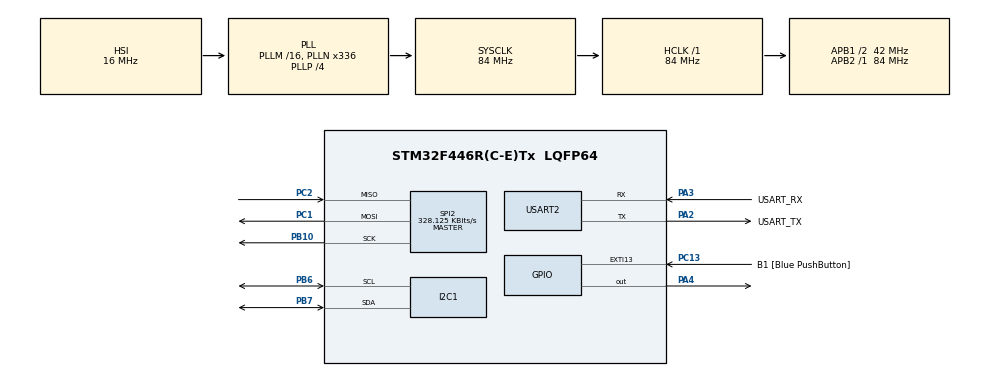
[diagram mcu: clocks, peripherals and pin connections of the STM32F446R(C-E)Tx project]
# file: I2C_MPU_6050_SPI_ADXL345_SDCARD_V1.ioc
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Mcu.Family=STM32F4
Mcu.Name=STM32F446R(C-E)Tx
Mcu.Package=LQFP64
NVIC.PriorityGroup=NVIC_PRIORITYGROUP_0
PA13.GPIO_Label=TMS
PA13.Mode=Serial_Wire
PA13.Signal=SYS_JTMS-SWDIO
PA14.GPIO_Label=TCK
PA14.Mode=Serial_Wire
PA14.Signal=SYS_JTCK-SWCLK
PA2.GPIO_Label=USART_TX
PA2.Mode=Asynchronous
PA2.Signal=USART2_TX
PA3.GPIO_Label=USART_RX
PA3.Mode=Asynchronous
PA3.Signal=USART2_RX
PA4.Signal=GPIO_Output
PB10.Mode=Full_Duplex_Master
PB10.Signal=SPI2_SCK
PB3.GPIO_Label=SWO
PB3.Signal=SYS_JTDO-SWO
PB6.Mode=I2C
PB6.Signal=I2C1_SCL
PB7.Mode=I2C
PB7.Signal=I2C1_SDA
PC1.Mode=Full_Duplex_Master
PC1.Signal=SPI2_MOSI
PC13.GPIO_Label=B1 [Blue PushButton]
PC13.GPIO_ModeDefaultEXTI=GPIO_MODE_IT_FALLING
PC13.Signal=GPXTI13
PC14-OSC32_IN.Mode=LSE-External-Oscillator
PC14-OSC32_IN.Signal=RCC_OSC32_IN
PC15-OSC32_OUT.Mode=LSE-External-Oscillator
PC15-OSC32_OUT.Signal=RCC_OSC32_OUT
PC2.Mode=Full_Duplex_Master
PC2.Signal=SPI2_MISO
PH0-OSC_IN.Mode=HSE-External-Oscillator
PH0-OSC_IN.Signal=RCC_OSC_IN
PH1-OSC_OUT.Mode=HSE-External-Oscillator
PH1-OSC_OUT.Signal=RCC_OSC_OUT
ProjectManager.HeapSize=0x200
ProjectManager.StackSize=0x400
ProjectManager.TargetToolchain=STM32CubeIDE
RCC.48MHZClocksFreq_Value=84000000
RCC.AHBFreq_Value=84000000
RCC.APB1CLKDivider=RCC_HCLK_DIV2
RCC.APB1Freq_Value=42000000
RCC.APB1TimFreq_Value=84000000
RCC.APB2Freq_Value=84000000
RCC.APB2TimFreq_Value=84000000
RCC.CortexFreq_Value=84000000
RCC.FLatency-AdvancedSettings=FLASH_LATENCY_2
RCC.HCLKFreq_Value=84000000
RCC.HSE_VALUE=8000000
RCC.HSI_VALUE=16000000
RCC.PLLN=336
RCC.PLLP=RCC_PLLP_DIV4
RCC.SYSCLKFreq_VALUE=84000000
RCC.SYSCLKSource=RCC_SYSCLKSOURCE_PLLCLK
RCC.USBFreq_Value=168000000
RCC.VCOOutputFreq_Value=336000000
SPI2.BaudRatePrescaler=SPI_BAUDRATEPRESCALER_128
SPI2.CalculateBaudRate=328.125 KBits/s
SPI2.Direction=SPI_DIRECTION_2LINES
SPI2.Mode=SPI_MODE_MASTER
SPI2.VirtualType=VM_MASTER
USART2.VirtualMode=VM_ASYNC
VP_FATFS_VS_Generic.Mode=User_defined
board=NUCLEO-F446RE

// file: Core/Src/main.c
/* USER CODE BEGIN Header */
/**
  ******************************************************************************
  * @file           : main.c
  * @brief          : Main program body
  ******************************************************************************
  * @attention
  *
  * Copyright (c) 2025 STMicroelectronics.
  * All rights reserved.
  *
  * This software is licensed under terms that can be found in the LICENSE file
  * in the root directory of this software component.
  * If no LICENSE file comes with this software, it is provided AS-IS.
  *
  ******************************************************************************
  */
/* USER CODE END Header */

// ===============================
//   INTERCONEXIONES STM32F446RE
// ===============================
//
// --- MPU6050 (I2C1) ---
// VCC   -> 3.3V                  // Alimentación del sensor
// GND   -> GND                   // Tierra
// SDA   -> PB7                   // I2C1_SDA (requiere pull-up 4.7kΩ)
// SCL   -> PB6                   // I2C1_SCL (requiere pull-up 4.7kΩ)
// AD0   -> GND                   // Dirección I2C = 0x68
// INT   -> (no conectado)        // Interrupción opcional
//
//
// --- Tarjeta SD (SPI2) ---
// VCC   -> 3.3V                  // Alimentación (¡no usar 5V!)
// GND   -> GND                   // Tierra
// CS    -> PA4                   // GPIO Output, Chip Select manual
// SCK   -> PB10                  // SPI2_SCK
// MISO  -> PC2                  // SPI2_MISO
// MOSI  -> PC1                  // SPI2_MOSI
//
//====================== INTERCONEXIÓN ADXL345 - STM32F446RE ======================//
// ADXL345        ->  STM32F446RE                // DESCRIPCIÓN
// ----------------------------------------------------------------------------- //
/* VCC           ->  3.3V                        // Alimentación del sensor     */
/* GND           ->  GND                         // Tierra común                */
/* CS            ->  PA9                         // Chip Select (CS) manual     */
/* SCL (CLK)     ->  PA5                         // SPI1_SCK - reloj SPI        */
/* SDA (MOSI)    ->  PA7                         // SPI1_MOSI - datos al sensor */
/* SDO (MISO)    ->  PA6                         // SPI1_MISO - datos al STM32  */
//================================================================================//

// ============================================
//   CONEXIONES STM32F446RE ↔ LCD I2C (PCF8574)
// ============================================
//
// LCD I2C     ↔   STM32F446RE
//
// VCC         ↔   5V               // Alimentación (verifica compatibilidad)
// GND         ↔   GND              // Tierra común
// SDA         ↔   PB7              // I2C1 SDA (requiere pull-up si el módulo no lo tiene)
// SCL         ↔   PB6              // I2C1 SCL (requiere pull-up si el módulo no lo tiene)

#include "main.h"
#include <stdio.h>
#include "stm32f4xx_hal.h"
#include "fatfs.h"
#include <string.h>
#include <stdint.h>
#include "adxl345.h"
#include "API_delay.h"
#include "lcd_i2c.h"

/* USER CODE BEGIN PTD */
typedef enum {
    ESTADO_IDLE,
    ESTADO_MPU,
    ESTADO_ADXL,
    ESTADO_SD,
	ESTADO_BORRAR_SD,
	ESTADO_LEER_SD,
	ESTADO_LCD,
    ESTADO_ERROR
} estado_t;

estado_t estadoActual = ESTADO_IDLE;

/* USER CODE END PTD */

I2C_HandleTypeDef hi2c1;

SPI_HandleTypeDef hspi2;

UART_HandleTypeDef huart2;

delay_t myDelayMPU,myDelayADXL,myDelaySD;

//extern I2C_HandleTypeDef hi2c1;

/* USER CODE BEGIN PV */
// === DEFINICIONES MPU6050 ===
#define MPU6050_ADDR  (0x68 << 1)
#define MPU6050_PWR_MGMT_1  0x6B
#define MPU6050_ACCEL_XOUT_H  0x3B

//extern I2C_HandleTypeDef hi2c1;
//extern UART_HandleTypeDef huart2;
//extern DMA_HandleTypeDef hdma_i2c1_rx;
int16_t AccX, AccY, AccZ, Temp, GyroX, GyroY, GyroZ;
float Ax, Ay, Az, Gx, Gy, Gz, TempC;
char msg[150];
char msg2[128];

// FATFS
FATFS fs;
FATFS *pfs;
FIL fil;
FRESULT fres;
DWORD fre_clust;
uint32_t totalSpace, freeSpace;
char buffer[200];
uint8_t rxChar;
char mensajeRoca[] = "La Roca dice: No te rindas, campeon\n";

int16_t x, y, z;          /**< Variables enteras para datos crudos de aceleración. */
double xg, yg, zg;        /**< Variables para datos de aceleración en g. */
uint8_t data_rec[6];      /**< Arreglo para almacenar los 6 bytes de datos del ADXL345. */

/* USER CODE END PV */
/* USER CODE BEGIN 0 */
void MPU6050_Init(void);
void MPU6050_Read_All(void);

void MPU6050_Init(void)
{
  uint8_t data = 0x00;
  HAL_I2C_Mem_Write(&hi2c1, MPU6050_ADDR, MPU6050_PWR_MGMT_1,
                    I2C_MEMADD_SIZE_8BIT, &data, 1, HAL_MAX_DELAY);
}

void MPU6050_Read_All(void)
{
  uint8_t raw_data[14];

  HAL_I2C_Mem_Read(&hi2c1, MPU6050_ADDR, MPU6050_ACCEL_XOUT_H,I2C_MEMADD_SIZE_8BIT, raw_data, 14, HAL_MAX_DELAY);

  // HAL_I2C_Mem_Read(
  //   &hi2c1,                   // I2C que estás usando (I2C1)
  //   MPU6050_ADDR,            // Dirección del sensor (0x68 << 1 = 0xD0)
  //   MPU6050_ACCEL_XOUT_H,    // Registro inicial: 0x3B (donde comienza AccX)
  //   I2C_MEMADD_SIZE_8BIT,    // Tamaño de dirección del registro (8 bits)
  //   raw_data,                // Buffer donde se guardan los 14 bytes leídos
  //   14,                      // Cantidad de bytes a leer (Acc, Temp, Gyro)
  //   HAL_MAX_DELAY            // Esperar indefinidamente si el bus está ocupado
  // );

    AccX = (raw_data[0] << 8) | raw_data[1];
    AccY = (raw_data[2] << 8) | raw_data[3];
    AccZ = (raw_data[4] << 8) | raw_data[5];
    Temp = (raw_data[6] << 8) | raw_data[7];
    GyroX = (raw_data[8] << 8) | raw_data[9];
    GyroY = (raw_data[10] << 8) | raw_data[11];
    GyroZ = (raw_data[12] << 8) | raw_data[13];

    Ax = AccX / 16384.0f; //convierte a datos crudos en unidades de medidas m/s2
    Ay = AccY / 16384.0f;
    Az = AccZ / 16384.0f;
    TempC = Temp / 340.0f + 36.53f;
    Gx = GyroX / 131.0f;
    Gy = GyroY / 131.0f;
    Gz = GyroZ / 131.0f;

}
/* USER CODE END 0 */

void SystemClock_Config(void);
static void MX_GPIO_Init(void);
static void MX_USART2_UART_Init(void);
static void MX_I2C1_Init(void);
static void MX_SPI2_Init(void);
void MX_FATFS_Init(void);
/* USER CODE BEGIN PFP */
void leerMPU(void);
void leerADXL(void);
void inicializarArchivoSD(void);
void borrarSD(void);
void leerSD(void);

/* USER CODE END PFP */

int main(void)
{

  /* MCU Configuration--------------------------------------------------------*/

  /* Reset of all peripherals, Initializes the Flash interface and the Systick. */
  HAL_Init();

  /* Configure the system clock */
  SystemClock_Config();

  /* Initialize all configured peripherals */
  MX_GPIO_Init();
  MX_USART2_UART_Init();
  MX_I2C1_Init();
  MX_SPI2_Init();
  MX_FATFS_Init();
  /* USER CODE BEGIN 2 */
  MPU6050_Init();
  adxl_init();  /**< Inicializa el acelerómetro ADXL345. */
  HAL_Delay(100);

  delayInit(&myDelayMPU, 1000);
  delayInit(&myDelayADXL, 500);
  delayInit(&myDelaySD, 2000);  // Ej. 2 segundos entre escrituras

  inicializarArchivoSD();

  LCD_Init(&hi2c1);

  /* USER CODE END 2 */

  /* Infinite loop */
  /* USER CODE BEGIN WHILE */
  while (1)
    {
	  switch (estadoActual)
	  {
	      case ESTADO_IDLE:
	          if (HAL_UART_Receive(&huart2, &rxChar, 1, 10) == HAL_OK) {
	              if (rxChar == '1') estadoActual = ESTADO_MPU;
	              else if (rxChar == '2') estadoActual = ESTADO_ADXL;
	              else if (rxChar == '3') estadoActual = ESTADO_SD;
	              else if (rxChar == '4') estadoActual = ESTADO_BORRAR_SD;
	              else if (rxChar == '5') estadoActual = ESTADO_LEER_SD;
	              else if (rxChar == '6') estadoActual = ESTADO_LCD; //NO CONCLUIDO
	              else estadoActual = ESTADO_IDLE;
	          }
	          break;

	      case ESTADO_MPU:
	    	  if (delayRead(&myDelayMPU))
	    	  {
	    		 leerMPU();
				 estadoActual = ESTADO_IDLE;
	    	  }
	          break;

	      case ESTADO_ADXL:
	    	  if (delayRead(&myDelayADXL))
	    	  {
	    		  leerADXL();
				  estadoActual = ESTADO_IDLE;
	    	  }
	          break;

	      case ESTADO_SD:
	    	  if (delayRead(&myDelaySD))
	    	  {
	    		  guardarDatosEnSD();
	    		  estadoActual = ESTADO_IDLE;
	    	  }
	          break;

	      case ESTADO_BORRAR_SD:
	    	  borrarSD();
	    	  break;

	      case ESTADO_LEER_SD:
	    	  leerSD();
	    	  break;

	      case ESTADO_LCD:
	    	   LCD_SendCommand(&hi2c1, 0x01);  // Limpiar pantalla
	    	   HAL_Delay(2);
	    	   LCD_SendString(&hi2c1, "Hola Mundo!");
	      	   estadoActual = ESTADO_IDLE;
	      	   break;

	      case ESTADO_ERROR:
	          HAL_UART_Transmit(&huart2, (uint8_t*)" Error detectado!\r\n", 19, HAL_MAX_DELAY);
	          estadoActual = ESTADO_IDLE;
	          break;

	      default:
	          estadoActual = ESTADO_IDLE;
	          break;
	  }

    }
  /* USER CODE END 3 */
}

void leerMPU(void)
{
  MPU6050_Read_All();
  int bytes = snprintf(msg, sizeof(msg),
						   "MPU Acelerometro[g]:  X=%.4f  Y=%.4f  Z=%.4f\r\n"
						   "MPU Giroscopio[gr/s]: X=%.4f  Y=%.4f  Z=%.4f\r\n"
						   "MPU Temperatura[C]:   %.2f\r\n\r\n",
						   Ax, Ay, Az, Gx, Gy, Gz, TempC);
   if (bytes > 0)
   {
	   HAL_UART_Transmit(&huart2, (uint8_t*)msg, bytes, HAL_MAX_DELAY);
   }
}

void leerADXL(void)
{
	adxl_read(DATA_START_ADDR, data_rec);
	x = ((data_rec[1] << 8) | data_rec[0]);
	y = ((data_rec[3] << 8) | data_rec[2]);
	z = ((data_rec[5] << 8) | data_rec[4]);
	xg = x * 0.0078;
	yg = y * 0.0078;
	zg = z * 0.0078;
	int bytes = snprintf(msg2, sizeof(msg2), "ADXL345[g]: X=%.4f  Y=%.4f  Z=%.4f\r\n\r\n", xg, yg, zg);
	if (bytes > 0)
	{
	  HAL_UART_Transmit(&huart2, (uint8_t*)msg2, bytes, HAL_MAX_DELAY);
	}
}

void inicializarArchivoSD(void)
{
    if (f_mount(&fs, "", 0) != FR_OK) Error_Handler();

    if (f_open(&fil, "la_roca.txt", FA_OPEN_ALWAYS | FA_READ | FA_WRITE) != FR_OK)
        Error_Handler();

    // Opcional: verificar espacio
    if (f_getfree("", &fre_clust, &pfs) != FR_OK) Error_Handler();
    totalSpace = (uint32_t)((pfs->n_fatent - 2) * pfs->csize * 0.5);
    freeSpace = (uint32_t)(fre_clust * pfs->csize * 0.5);
    if (freeSpace < 1) Error_Handler();

    // Escribir datos iniciales
    f_puts("CESE\n", &fil);
    f_puts("STM32F446RE SD Card via SPI2\n", &fil);
    f_puts("Cristo la Roca!!!\r\n", &fil);

    if (f_close(&fil) != FR_OK) Error_Handler();

    // Lectura opcional
    if (f_open(&fil, "la_roca.txt", FA_READ) != FR_OK) Error_Handler();
    while (f_gets(buffer, sizeof(buffer), &fil)) {
    	HAL_UART_Transmit(&huart2, (uint8_t*)buffer, strlen(buffer), HAL_MAX_DELAY);
    }
    if (f_close(&fil) != FR_OK) Error_Handler();

    if (f_mount(NULL, "", 1) != FR_OK) Error_Handler();
}

void guardarDatosEnSD(void)
{
    if (f_mount(&fs, "", 0) != FR_OK) {
        estadoActual = ESTADO_ERROR;
        return;
    }

    if (f_open(&fil, "la_roca.txt", FA_OPEN_APPEND | FA_WRITE) != FR_OK) {
        estadoActual = ESTADO_ERROR;
        return;
    }

    f_puts(msg, &fil);
    f_puts(msg2, &fil);
    f_close(&fil);
    f_mount(NULL, "", 1);

    HAL_UART_Transmit(&huart2, (uint8_t*)"Datos guardados en SD.\r\n", 25, HAL_MAX_DELAY);

}

void borrarSD(void)
{
    if (f_mount(&fs, "", 0) == FR_OK)
    {
        if (f_open(&fil, "la_roca.txt", FA_WRITE | FA_CREATE_ALWAYS) == FR_OK)
        {
            // ✅ Archivo truncado (contenido eliminado)
            f_puts("Archivo reiniciado.\r\n", &fil);  // Opcional: escribir línea de cabecera
            f_close(&fil);
            char msg[] = "Contenido del archivo borrado.\r\n";
            HAL_UART_Transmit(&huart2, (uint8_t*)msg, strlen(msg), HAL_MAX_DELAY);
        }
        else
        {
            estadoActual = ESTADO_ERROR;
            return;
        }
        f_mount(NULL, "", 1);
    } else {
        estadoActual = ESTADO_ERROR;
        return;
    }
    estadoActual = ESTADO_IDLE;
}

void leerSD(void)
{
    if (f_mount(&fs, "", 0) == FR_OK)
    {
        if (f_open(&fil, "la_roca.txt", FA_READ) == FR_OK)
        {
            while (f_gets(buffer, sizeof(buffer), &fil))
            {
                HAL_UART_Transmit(&huart2, (uint8_t*)buffer, strlen(buffer), HAL_MAX_DELAY);
            }
            f_close(&fil);
            char fin[] = "\r\nFin de lectura SD\r\n";
            HAL_UART_Transmit(&huart2, (uint8_t*)fin, strlen(fin), HAL_MAX_DELAY);
        }
        else
        {
            estadoActual = ESTADO_ERROR;
            return;
        }
        f_mount(NULL, "", 1);
    }
    else
    {
        estadoActual = ESTADO_ERROR;
        return;
    }
    estadoActual = ESTADO_IDLE;
}

void SystemClock_Config(void)
{
  RCC_OscInitTypeDef RCC_OscInitStruct = {0};
  RCC_ClkInitTypeDef RCC_ClkInitStruct = {0};

  /** Configure the main internal regulator output voltage
  */
  __HAL_RCC_PWR_CLK_ENABLE();
  __HAL_PWR_VOLTAGESCALING_CONFIG(PWR_REGULATOR_VOLTAGE_SCALE3);

  /** Initializes the RCC Oscillators according to the specified parameters
  * in the RCC_OscInitTypeDef structure.
  */
  RCC_OscInitStruct.OscillatorType = RCC_OSCILLATORTYPE_HSI;
  RCC_OscInitStruct.HSIState = RCC_HSI_ON;
  RCC_OscInitStruct.HSICalibrationValue = RCC_HSICALIBRATION_DEFAULT;
  RCC_OscInitStruct.PLL.PLLState = RCC_PLL_ON;
  RCC_OscInitStruct.PLL.PLLSource = RCC_PLLSOURCE_HSI;
  RCC_OscInitStruct.PLL.PLLM = 16;
  RCC_OscInitStruct.PLL.PLLN = 336;
  RCC_OscInitStruct.PLL.PLLP = RCC_PLLP_DIV4;
  RCC_OscInitStruct.PLL.PLLQ = 2;
  RCC_OscInitStruct.PLL.PLLR = 2;
  if (HAL_RCC_OscConfig(&RCC_OscInitStruct) != HAL_OK)
  {
    Error_Handler();
  }

  /** Initializes the CPU, AHB and APB buses clocks
  */
  RCC_ClkInitStruct.ClockType = RCC_CLOCKTYPE_HCLK|RCC_CLOCKTYPE_SYSCLK
                              |RCC_CLOCKTYPE_PCLK1|RCC_CLOCKTYPE_PCLK2;
  RCC_ClkInitStruct.SYSCLKSource = RCC_SYSCLKSOURCE_PLLCLK;
  RCC_ClkInitStruct.AHBCLKDivider = RCC_SYSCLK_DIV1;
  RCC_ClkInitStruct.APB1CLKDivider = RCC_HCLK_DIV2;
  RCC_ClkInitStruct.APB2CLKDivider = RCC_HCLK_DIV1;

  if (HAL_RCC_ClockConfig(&RCC_ClkInitStruct, FLASH_LATENCY_2) != HAL_OK)
  {
    Error_Handler();
  }
}

static void MX_I2C1_Init(void)
{

  hi2c1.Instance = I2C1;
  hi2c1.Init.ClockSpeed = 100000;
  hi2c1.Init.DutyCycle = I2C_DUTYCYCLE_2;
  hi2c1.Init.OwnAddress1 = 0;
  hi2c1.Init.AddressingMode = I2C_ADDRESSINGMODE_7BIT;
  hi2c1.Init.DualAddressMode = I2C_DUALADDRESS_DISABLE;
  hi2c1.Init.OwnAddress2 = 0;
  hi2c1.Init.GeneralCallMode = I2C_GENERALCALL_DISABLE;
  hi2c1.Init.NoStretchMode = I2C_NOSTRETCH_DISABLE;
  if (HAL_I2C_Init(&hi2c1) != HAL_OK)
  {
    Error_Handler();
  }

}

static void MX_SPI2_Init(void)
{

  /* SPI2 parameter configuration*/
  hspi2.Instance = SPI2;
  hspi2.Init.Mode = SPI_MODE_MASTER;
  hspi2.Init.Direction = SPI_DIRECTION_2LINES;
  hspi2.Init.DataSize = SPI_DATASIZE_8BIT;
  hspi2.Init.CLKPolarity = SPI_POLARITY_LOW;
  hspi2.Init.CLKPhase = SPI_PHASE_1EDGE;
  hspi2.Init.NSS = SPI_NSS_SOFT;
  hspi2.Init.BaudRatePrescaler = SPI_BAUDRATEPRESCALER_128;
  hspi2.Init.FirstBit = SPI_FIRSTBIT_MSB;
  hspi2.Init.TIMode = SPI_TIMODE_DISABLE;
  hspi2.Init.CRCCalculation = SPI_CRCCALCULATION_DISABLE;
  hspi2.Init.CRCPolynomial = 10;
  if (HAL_SPI_Init(&hspi2) != HAL_OK)
  {
    Error_Handler();
  }

}

static void MX_USART2_UART_Init(void)
{

  huart2.Instance = USART2;
  huart2.Init.BaudRate = 115200;
  huart2.Init.WordLength = UART_WORDLENGTH_8B;
  huart2.Init.StopBits = UART_STOPBITS_1;
  huart2.Init.Parity = UART_PARITY_NONE;
  huart2.Init.Mode = UART_MODE_TX_RX;
  huart2.Init.HwFlowCtl = UART_HWCONTROL_NONE;
  huart2.Init.OverSampling = UART_OVERSAMPLING_16;
  if (HAL_UART_Init(&huart2) != HAL_OK)
  {
    Error_Handler();
  }

}

static void MX_GPIO_Init(void)
{
  GPIO_InitTypeDef GPIO_InitStruct = {0};

  /* GPIO Ports Clock Enable */
  __HAL_RCC_GPIOC_CLK_ENABLE();
  __HAL_RCC_GPIOH_CLK_ENABLE();
  __HAL_RCC_GPIOA_CLK_ENABLE();
  __HAL_RCC_GPIOB_CLK_ENABLE();

  //Configure GPIO pin Output Level
  HAL_GPIO_WritePin(GPIOA, GPIO_PIN_4, GPIO_PIN_RESET);

  /*Configure GPIO pin : B1_Pin */
  GPIO_InitStruct.Pin = B1_Pin;
  GPIO_InitStruct.Mode = GPIO_MODE_IT_FALLING;
  GPIO_InitStruct.Pull = GPIO_NOPULL;
  HAL_GPIO_Init(B1_GPIO_Port, &GPIO_InitStruct);

  //Configure GPIO pin : PA4
  GPIO_InitStruct.Pin = GPIO_PIN_4;
  GPIO_InitStruct.Mode = GPIO_MODE_OUTPUT_PP;
  GPIO_InitStruct.Pull = GPIO_NOPULL;
  GPIO_InitStruct.Speed = GPIO_SPEED_FREQ_LOW;
  HAL_GPIO_Init(GPIOA, &GPIO_InitStruct);

  // Configure SPI2 GPIOs: PB13=SCK, PB14=MISO, PB15=MOSI
  GPIO_InitStruct.Pin = GPIO_PIN_13 | GPIO_PIN_14 | GPIO_PIN_15;
  GPIO_InitStruct.Mode = GPIO_MODE_AF_PP;
  GPIO_InitStruct.Pull = GPIO_NOPULL; // Si tu módulo SD no tiene pull-up en MISO, considera PULLUP aquí
  GPIO_InitStruct.Speed = GPIO_SPEED_FREQ_VERY_HIGH;
  GPIO_InitStruct.Alternate = GPIO_AF5_SPI2;
  HAL_GPIO_Init(GPIOB, &GPIO_InitStruct);

}

void Error_Handler(void)
{
  __disable_irq();
  while (1)
  {
  }
}
